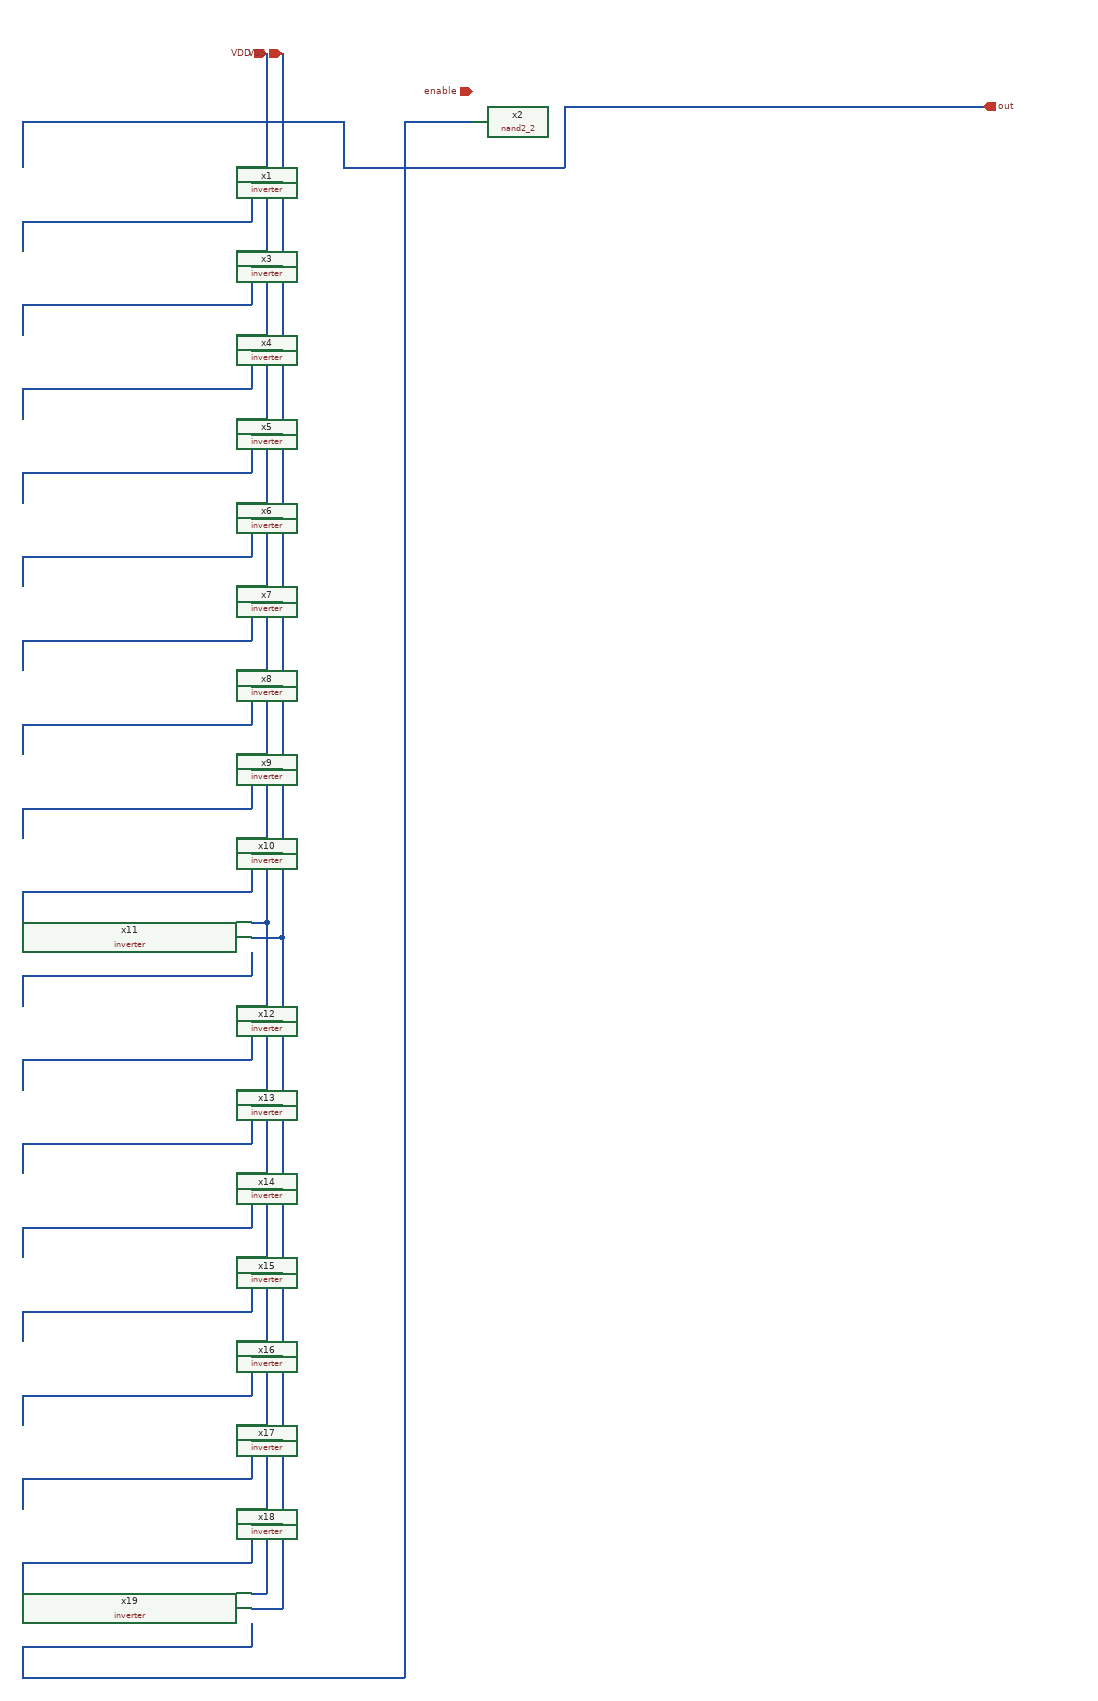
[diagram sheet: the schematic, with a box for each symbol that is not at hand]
v {xschem version=3.4.5 file_version=1.2
}
G {}
K {}
V {}
S {}
E {}
N -80 120 210 120 {
lab=pre_drive}
N -200 120 -180 120 {
lab=VDD}
N -200 140 -160 140 {
lab=VSS}
N -200 160 -200 190 {
lab=#net2}
N -500 190 -200 190 {
lab=#net2}
N -500 190 -500 230 {
lab=#net2}
N -200 230 -180 230 {
lab=VDD}
N -200 250 -160 250 {
lab=VSS}
N -200 270 -200 300 {
lab=#net3}
N -500 300 -200 300 {
lab=#net3}
N -500 300 -500 340 {
lab=#net3}
N -200 340 -180 340 {
lab=VDD}
N -200 360 -160 360 {
lab=VSS}
N -200 380 -200 410 {
lab=#net4}
N -500 410 -200 410 {
lab=#net4}
N -500 410 -500 450 {
lab=#net4}
N -200 450 -180 450 {
lab=VDD}
N -200 470 -160 470 {
lab=VSS}
N -200 490 -200 520 {
lab=#net5}
N -500 520 -200 520 {
lab=#net5}
N -500 520 -500 560 {
lab=#net5}
N -200 560 -180 560 {
lab=VDD}
N -200 580 -160 580 {
lab=VSS}
N -200 600 -200 630 {
lab=#net6}
N -500 630 -200 630 {
lab=#net6}
N -500 630 -500 670 {
lab=#net6}
N -200 670 -180 670 {
lab=VDD}
N -200 690 -160 690 {
lab=VSS}
N -200 710 -200 740 {
lab=#net7}
N -500 740 -200 740 {
lab=#net7}
N -500 740 -500 780 {
lab=#net7}
N -200 780 -180 780 {
lab=VDD}
N -200 800 -160 800 {
lab=VSS}
N -200 820 -200 850 {
lab=#net8}
N -500 850 -200 850 {
lab=#net8}
N -500 850 -500 890 {
lab=#net8}
N -200 890 -180 890 {
lab=VDD}
N -200 910 -160 910 {
lab=VSS}
N -200 930 -200 960 {
lab=#net9}
N -500 960 -200 960 {
lab=#net9}
N -500 960 -500 1000 {
lab=#net9}
N -200 1000 -180 1000 {
lab=VDD}
N -200 1020 -160 1020 {
lab=VSS}
N -200 1040 -200 1070 {
lab=#net10}
N -500 1070 -200 1070 {
lab=#net10}
N -500 1070 -500 1110 {
lab=#net10}
N -200 1110 -180 1110 {
lab=VDD}
N -200 1130 -160 1130 {
lab=VSS}
N -200 1150 -200 1180 {
lab=#net11}
N -500 1180 -200 1180 {
lab=#net11}
N -500 1180 -500 1220 {
lab=#net11}
N -160 -30 -160 1130 {
lab=VSS}
N -180 -30 -180 1110 {
lab=VDD}
N -200 1220 -180 1220 {
lab=VDD}
N -200 1240 -160 1240 {
lab=VSS}
N -200 1260 -200 1290 {
lab=#net12}
N -500 1290 -200 1290 {
lab=#net12}
N -500 1290 -500 1330 {
lab=#net12}
N -200 1330 -180 1330 {
lab=VDD}
N -200 1350 -160 1350 {
lab=VSS}
N -200 1370 -200 1400 {
lab=#net13}
N -500 1400 -200 1400 {
lab=#net13}
N -500 1400 -500 1440 {
lab=#net13}
N -200 1440 -180 1440 {
lab=VDD}
N -200 1460 -160 1460 {
lab=VSS}
N -200 1480 -200 1510 {
lab=#net14}
N -500 1510 -200 1510 {
lab=#net14}
N -500 1510 -500 1550 {
lab=#net14}
N -200 1550 -180 1550 {
lab=VDD}
N -200 1570 -160 1570 {
lab=VSS}
N -200 1590 -200 1620 {
lab=#net15}
N -500 1620 -200 1620 {
lab=#net15}
N -500 1620 -500 1660 {
lab=#net15}
N -200 1660 -180 1660 {
lab=VDD}
N -200 1680 -160 1680 {
lab=VSS}
N -200 1700 -200 1730 {
lab=#net16}
N -500 1730 -200 1730 {
lab=#net16}
N -500 1730 -500 1770 {
lab=#net16}
N -200 1770 -180 1770 {
lab=VDD}
N -200 1790 -160 1790 {
lab=VSS}
N -200 1810 -200 1840 {
lab=#net17}
N -500 1840 -200 1840 {
lab=#net17}
N -500 1840 -500 1880 {
lab=#net17}
N -200 1880 -180 1880 {
lab=VDD}
N -200 1900 -160 1900 {
lab=VSS}
N -200 1920 -200 1950 {
lab=#net18}
N -500 1950 -200 1950 {
lab=#net18}
N -500 1950 -500 1990 {
lab=#net18}
N -200 1990 -180 1990 {
lab=VDD}
N -200 2010 -160 2010 {
lab=VSS}
N -200 2030 -200 2060 {
lab=#net19}
N -500 2060 -200 2060 {
lab=#net19}
N -500 2060 -500 2100 {
lab=#net19}
N -180 1110 -180 1990 {
lab=VDD}
N -160 1130 -160 2010 {
lab=VSS}
N -500 2100 -0 2100 {
lab=#net19}
N 0 60 0 2100 {
lab=#net19}
N 0 60 90 60 {
lab=#net19}
N -80 60 -80 120 {
lab=pre_drive}
N -500 60 -80 60 {
lab=pre_drive}
N -500 60 -500 120 {
lab=pre_drive}
N 660 40 760 40 {
lab=out}
N 210 40 210 120 {}
N 210 40 660 40 {}
C {devices/iopin.sym} -180 -30 2 0 {name=p1 lab=VDD
}
C {devices/ipin.sym} 90 20 0 0 {name=p3 lab=enable}
C {sky130_stdcells/nand2_2.sym} 150 40 0 0 {name=x2 VGND=VSS VNB=VSS VPB=VDD VPWR=VDD prefix=sky130_fd_sc_hd__ }
C {inverter.sym} -350 140 0 0 {name=x1}
C {inverter.sym} -350 250 0 0 {name=x3}
C {inverter.sym} -350 360 0 0 {name=x4}
C {inverter.sym} -350 470 0 0 {name=x5}
C {inverter.sym} -350 580 0 0 {name=x6}
C {inverter.sym} -350 690 0 0 {name=x7}
C {inverter.sym} -350 800 0 0 {name=x8}
C {inverter.sym} -350 910 0 0 {name=x9}
C {inverter.sym} -350 1020 0 0 {name=x10}
C {inverter.sym} -350 1130 0 0 {name=x11}
C {devices/iopin.sym} -160 -30 0 0 {name=p2 lab=VSS
}
C {inverter.sym} -350 1240 0 0 {name=x12}
C {inverter.sym} -350 1350 0 0 {name=x13}
C {inverter.sym} -350 1460 0 0 {name=x14}
C {inverter.sym} -350 1570 0 0 {name=x15}
C {inverter.sym} -350 1680 0 0 {name=x16}
C {inverter.sym} -350 1790 0 0 {name=x17}
C {inverter.sym} -350 1900 0 0 {name=x18}
C {inverter.sym} -350 2010 0 0 {name=x19}
C {devices/opin.sym} 760 40 0 0 {name=p10 lab=out}
